VERSION 5.7 ;
BUSBITCHARS "[]" ;
DIVIDERCHAR "/" ;

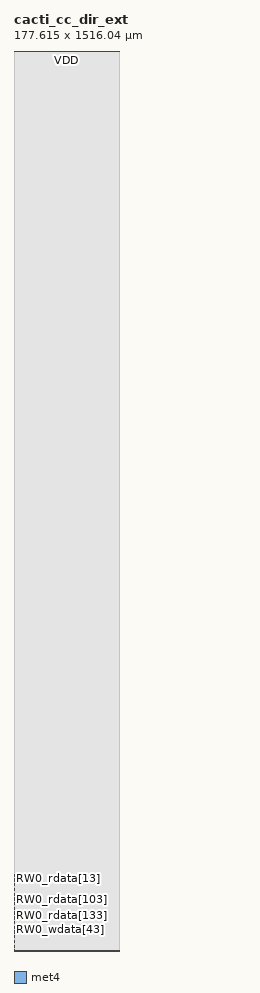
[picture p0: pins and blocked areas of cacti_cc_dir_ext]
MACRO cacti_cc_dir_ext
  CLASS BLOCK BLACKBOX ;
  ORIGIN 0 0 ;
  FOREIGN cacti_cc_dir_ext 0 0 ;
  SIZE 177.615 BY 1516.040 ;
  SYMMETRY X Y ;

  PIN VDD
    DIRECTION INOUT ;
    USE POWER ;
    PORT
      LAYER met4 ;
        RECT 0.000 1515.540 177.615 1516.040 ;
    END
  END VDD
  PIN VSS
    DIRECTION INOUT ;
    USE GROUND ;
    PORT
      LAYER met4 ;
        RECT 0.000 0.000 177.615 0.500 ;
    END
  END VSS
  PIN RW0_clk
    DIRECTION INPUT ;
    USE CLOCK ;
    PORT
      LAYER met4 ;
        RECT 0.000 0.700 0.200 0.900 ;
    END
  END RW0_clk
  PIN RW0_en
    DIRECTION INPUT ;
    USE SIGNAL ;
    PORT
      LAYER met4 ;
        RECT 0.000 1.100 0.200 1.300 ;
    END
  END RW0_en
  PIN RW0_wmode
    DIRECTION INPUT ;
    USE SIGNAL ;
    PORT
      LAYER met4 ;
        RECT 0.000 1.500 0.200 1.700 ;
    END
  END RW0_wmode
  PIN RW0_addr[9]
    DIRECTION INPUT ;
    USE SIGNAL ;
    PORT
      LAYER met4 ;
        RECT 0.000 1.900 0.200 2.100 ;
    END
  END RW0_addr[9]
  PIN RW0_addr[8]
    DIRECTION INPUT ;
    USE SIGNAL ;
    PORT
      LAYER met4 ;
        RECT 0.000 2.300 0.200 2.500 ;
    END
  END RW0_addr[8]
  PIN RW0_addr[7]
    DIRECTION INPUT ;
    USE SIGNAL ;
    PORT
      LAYER met4 ;
        RECT 0.000 2.700 0.200 2.900 ;
    END
  END RW0_addr[7]
  PIN RW0_addr[6]
    DIRECTION INPUT ;
    USE SIGNAL ;
    PORT
      LAYER met4 ;
        RECT 0.000 3.100 0.200 3.300 ;
    END
  END RW0_addr[6]
  PIN RW0_addr[5]
    DIRECTION INPUT ;
    USE SIGNAL ;
    PORT
      LAYER met4 ;
        RECT 0.000 3.500 0.200 3.700 ;
    END
  END RW0_addr[5]
  PIN RW0_addr[4]
    DIRECTION INPUT ;
    USE SIGNAL ;
    PORT
      LAYER met4 ;
        RECT 0.000 3.900 0.200 4.100 ;
    END
  END RW0_addr[4]
  PIN RW0_addr[3]
    DIRECTION INPUT ;
    USE SIGNAL ;
    PORT
      LAYER met4 ;
        RECT 0.000 4.300 0.200 4.500 ;
    END
  END RW0_addr[3]
  PIN RW0_addr[2]
    DIRECTION INPUT ;
    USE SIGNAL ;
    PORT
      LAYER met4 ;
        RECT 0.000 4.700 0.200 4.900 ;
    END
  END RW0_addr[2]
  PIN RW0_addr[1]
    DIRECTION INPUT ;
    USE SIGNAL ;
    PORT
      LAYER met4 ;
        RECT 0.000 5.100 0.200 5.300 ;
    END
  END RW0_addr[1]
  PIN RW0_addr[0]
    DIRECTION INPUT ;
    USE SIGNAL ;
    PORT
      LAYER met4 ;
        RECT 0.000 5.500 0.200 5.700 ;
    END
  END RW0_addr[0]
  PIN RW0_wdata[151]
    DIRECTION INPUT ;
    USE SIGNAL ;
    PORT
      LAYER met4 ;
        RECT 0.000 5.900 0.200 6.100 ;
    END
  END RW0_wdata[151]
  PIN RW0_wdata[150]
    DIRECTION INPUT ;
    USE SIGNAL ;
    PORT
      LAYER met4 ;
        RECT 0.000 6.300 0.200 6.500 ;
    END
  END RW0_wdata[150]
  PIN RW0_wdata[149]
    DIRECTION INPUT ;
    USE SIGNAL ;
    PORT
      LAYER met4 ;
        RECT 0.000 6.700 0.200 6.900 ;
    END
  END RW0_wdata[149]
  PIN RW0_wdata[148]
    DIRECTION INPUT ;
    USE SIGNAL ;
    PORT
      LAYER met4 ;
        RECT 0.000 7.100 0.200 7.300 ;
    END
  END RW0_wdata[148]
  PIN RW0_wdata[147]
    DIRECTION INPUT ;
    USE SIGNAL ;
    PORT
      LAYER met4 ;
        RECT 0.000 7.500 0.200 7.700 ;
    END
  END RW0_wdata[147]
  PIN RW0_wdata[146]
    DIRECTION INPUT ;
    USE SIGNAL ;
    PORT
      LAYER met4 ;
        RECT 0.000 7.900 0.200 8.100 ;
    END
  END RW0_wdata[146]
  PIN RW0_wdata[145]
    DIRECTION INPUT ;
    USE SIGNAL ;
    PORT
      LAYER met4 ;
        RECT 0.000 8.300 0.200 8.500 ;
    END
  END RW0_wdata[145]
  PIN RW0_wdata[144]
    DIRECTION INPUT ;
    USE SIGNAL ;
    PORT
      LAYER met4 ;
        RECT 0.000 8.700 0.200 8.900 ;
    END
  END RW0_wdata[144]
  PIN RW0_wdata[143]
    DIRECTION INPUT ;
    USE SIGNAL ;
    PORT
      LAYER met4 ;
        RECT 0.000 9.100 0.200 9.300 ;
    END
  END RW0_wdata[143]
  PIN RW0_wdata[142]
    DIRECTION INPUT ;
    USE SIGNAL ;
    PORT
      LAYER met4 ;
        RECT 0.000 9.500 0.200 9.700 ;
    END
  END RW0_wdata[142]
  PIN RW0_wdata[141]
    DIRECTION INPUT ;
    USE SIGNAL ;
    PORT
      LAYER met4 ;
        RECT 0.000 9.900 0.200 10.100 ;
    END
  END RW0_wdata[141]
  PIN RW0_wdata[140]
    DIRECTION INPUT ;
    USE SIGNAL ;
    PORT
      LAYER met4 ;
        RECT 0.000 10.300 0.200 10.500 ;
    END
  END RW0_wdata[140]
  PIN RW0_wdata[139]
    DIRECTION INPUT ;
    USE SIGNAL ;
    PORT
      LAYER met4 ;
        RECT 0.000 10.700 0.200 10.900 ;
    END
  END RW0_wdata[139]
  PIN RW0_wdata[138]
    DIRECTION INPUT ;
    USE SIGNAL ;
    PORT
      LAYER met4 ;
        RECT 0.000 11.100 0.200 11.300 ;
    END
  END RW0_wdata[138]
  PIN RW0_wdata[137]
    DIRECTION INPUT ;
    USE SIGNAL ;
    PORT
      LAYER met4 ;
        RECT 0.000 11.500 0.200 11.700 ;
    END
  END RW0_wdata[137]
  PIN RW0_wdata[136]
    DIRECTION INPUT ;
    USE SIGNAL ;
    PORT
      LAYER met4 ;
        RECT 0.000 11.900 0.200 12.100 ;
    END
  END RW0_wdata[136]
  PIN RW0_wdata[135]
    DIRECTION INPUT ;
    USE SIGNAL ;
    PORT
      LAYER met4 ;
        RECT 0.000 12.300 0.200 12.500 ;
    END
  END RW0_wdata[135]
  PIN RW0_wdata[134]
    DIRECTION INPUT ;
    USE SIGNAL ;
    PORT
      LAYER met4 ;
        RECT 0.000 12.700 0.200 12.900 ;
    END
  END RW0_wdata[134]
  PIN RW0_wdata[133]
    DIRECTION INPUT ;
    USE SIGNAL ;
    PORT
      LAYER met4 ;
        RECT 0.000 13.100 0.200 13.300 ;
    END
  END RW0_wdata[133]
  PIN RW0_wdata[132]
    DIRECTION INPUT ;
    USE SIGNAL ;
    PORT
      LAYER met4 ;
        RECT 0.000 13.500 0.200 13.700 ;
    END
  END RW0_wdata[132]
  PIN RW0_wdata[131]
    DIRECTION INPUT ;
    USE SIGNAL ;
    PORT
      LAYER met4 ;
        RECT 0.000 13.900 0.200 14.100 ;
    END
  END RW0_wdata[131]
  PIN RW0_wdata[130]
    DIRECTION INPUT ;
    USE SIGNAL ;
    PORT
      LAYER met4 ;
        RECT 0.000 14.300 0.200 14.500 ;
    END
  END RW0_wdata[130]
  PIN RW0_wdata[129]
    DIRECTION INPUT ;
    USE SIGNAL ;
    PORT
      LAYER met4 ;
        RECT 0.000 14.700 0.200 14.900 ;
    END
  END RW0_wdata[129]
  PIN RW0_wdata[128]
    DIRECTION INPUT ;
    USE SIGNAL ;
    PORT
      LAYER met4 ;
        RECT 0.000 15.100 0.200 15.300 ;
    END
  END RW0_wdata[128]
  PIN RW0_wdata[127]
    DIRECTION INPUT ;
    USE SIGNAL ;
    PORT
      LAYER met4 ;
        RECT 0.000 15.500 0.200 15.700 ;
    END
  END RW0_wdata[127]
  PIN RW0_wdata[126]
    DIRECTION INPUT ;
    USE SIGNAL ;
    PORT
      LAYER met4 ;
        RECT 0.000 15.900 0.200 16.100 ;
    END
  END RW0_wdata[126]
  PIN RW0_wdata[125]
    DIRECTION INPUT ;
    USE SIGNAL ;
    PORT
      LAYER met4 ;
        RECT 0.000 16.300 0.200 16.500 ;
    END
  END RW0_wdata[125]
  PIN RW0_wdata[124]
    DIRECTION INPUT ;
    USE SIGNAL ;
    PORT
      LAYER met4 ;
        RECT 0.000 16.700 0.200 16.900 ;
    END
  END RW0_wdata[124]
  PIN RW0_wdata[123]
    DIRECTION INPUT ;
    USE SIGNAL ;
    PORT
      LAYER met4 ;
        RECT 0.000 17.100 0.200 17.300 ;
    END
  END RW0_wdata[123]
  PIN RW0_wdata[122]
    DIRECTION INPUT ;
    USE SIGNAL ;
    PORT
      LAYER met4 ;
        RECT 0.000 17.500 0.200 17.700 ;
    END
  END RW0_wdata[122]
  PIN RW0_wdata[121]
    DIRECTION INPUT ;
    USE SIGNAL ;
    PORT
      LAYER met4 ;
        RECT 0.000 17.900 0.200 18.100 ;
    END
  END RW0_wdata[121]
  PIN RW0_wdata[120]
    DIRECTION INPUT ;
    USE SIGNAL ;
    PORT
      LAYER met4 ;
        RECT 0.000 18.300 0.200 18.500 ;
    END
  END RW0_wdata[120]
  PIN RW0_wdata[119]
    DIRECTION INPUT ;
    USE SIGNAL ;
    PORT
      LAYER met4 ;
        RECT 0.000 18.700 0.200 18.900 ;
    END
  END RW0_wdata[119]
  PIN RW0_wdata[118]
    DIRECTION INPUT ;
    USE SIGNAL ;
    PORT
      LAYER met4 ;
        RECT 0.000 19.100 0.200 19.300 ;
    END
  END RW0_wdata[118]
  PIN RW0_wdata[117]
    DIRECTION INPUT ;
    USE SIGNAL ;
    PORT
      LAYER met4 ;
        RECT 0.000 19.500 0.200 19.700 ;
    END
  END RW0_wdata[117]
  PIN RW0_wdata[116]
    DIRECTION INPUT ;
    USE SIGNAL ;
    PORT
      LAYER met4 ;
        RECT 0.000 19.900 0.200 20.100 ;
    END
  END RW0_wdata[116]
  PIN RW0_wdata[115]
    DIRECTION INPUT ;
    USE SIGNAL ;
    PORT
      LAYER met4 ;
        RECT 0.000 20.300 0.200 20.500 ;
    END
  END RW0_wdata[115]
  PIN RW0_wdata[114]
    DIRECTION INPUT ;
    USE SIGNAL ;
    PORT
      LAYER met4 ;
        RECT 0.000 20.700 0.200 20.900 ;
    END
  END RW0_wdata[114]
  PIN RW0_wdata[113]
    DIRECTION INPUT ;
    USE SIGNAL ;
    PORT
      LAYER met4 ;
        RECT 0.000 21.100 0.200 21.300 ;
    END
  END RW0_wdata[113]
  PIN RW0_wdata[112]
    DIRECTION INPUT ;
    USE SIGNAL ;
    PORT
      LAYER met4 ;
        RECT 0.000 21.500 0.200 21.700 ;
    END
  END RW0_wdata[112]
  PIN RW0_wdata[111]
    DIRECTION INPUT ;
    USE SIGNAL ;
    PORT
      LAYER met4 ;
        RECT 0.000 21.900 0.200 22.100 ;
    END
  END RW0_wdata[111]
  PIN RW0_wdata[110]
    DIRECTION INPUT ;
    USE SIGNAL ;
    PORT
      LAYER met4 ;
        RECT 0.000 22.300 0.200 22.500 ;
    END
  END RW0_wdata[110]
  PIN RW0_wdata[109]
    DIRECTION INPUT ;
    USE SIGNAL ;
    PORT
      LAYER met4 ;
        RECT 0.000 22.700 0.200 22.900 ;
    END
  END RW0_wdata[109]
  PIN RW0_wdata[108]
    DIRECTION INPUT ;
    USE SIGNAL ;
    PORT
      LAYER met4 ;
        RECT 0.000 23.100 0.200 23.300 ;
    END
  END RW0_wdata[108]
  PIN RW0_wdata[107]
    DIRECTION INPUT ;
    USE SIGNAL ;
    PORT
      LAYER met4 ;
        RECT 0.000 23.500 0.200 23.700 ;
    END
  END RW0_wdata[107]
  PIN RW0_wdata[106]
    DIRECTION INPUT ;
    USE SIGNAL ;
    PORT
      LAYER met4 ;
        RECT 0.000 23.900 0.200 24.100 ;
    END
  END RW0_wdata[106]
  PIN RW0_wdata[105]
    DIRECTION INPUT ;
    USE SIGNAL ;
    PORT
      LAYER met4 ;
        RECT 0.000 24.300 0.200 24.500 ;
    END
  END RW0_wdata[105]
  PIN RW0_wdata[104]
    DIRECTION INPUT ;
    USE SIGNAL ;
    PORT
      LAYER met4 ;
        RECT 0.000 24.700 0.200 24.900 ;
    END
  END RW0_wdata[104]
  PIN RW0_wdata[103]
    DIRECTION INPUT ;
    USE SIGNAL ;
    PORT
      LAYER met4 ;
        RECT 0.000 25.100 0.200 25.300 ;
    END
  END RW0_wdata[103]
  PIN RW0_wdata[102]
    DIRECTION INPUT ;
    USE SIGNAL ;
    PORT
      LAYER met4 ;
        RECT 0.000 25.500 0.200 25.700 ;
    END
  END RW0_wdata[102]
  PIN RW0_wdata[101]
    DIRECTION INPUT ;
    USE SIGNAL ;
    PORT
      LAYER met4 ;
        RECT 0.000 25.900 0.200 26.100 ;
    END
  END RW0_wdata[101]
  PIN RW0_wdata[100]
    DIRECTION INPUT ;
    USE SIGNAL ;
    PORT
      LAYER met4 ;
        RECT 0.000 26.300 0.200 26.500 ;
    END
  END RW0_wdata[100]
  PIN RW0_wdata[99]
    DIRECTION INPUT ;
    USE SIGNAL ;
    PORT
      LAYER met4 ;
        RECT 0.000 26.700 0.200 26.900 ;
    END
  END RW0_wdata[99]
  PIN RW0_wdata[98]
    DIRECTION INPUT ;
    USE SIGNAL ;
    PORT
      LAYER met4 ;
        RECT 0.000 27.100 0.200 27.300 ;
    END
  END RW0_wdata[98]
  PIN RW0_wdata[97]
    DIRECTION INPUT ;
    USE SIGNAL ;
    PORT
      LAYER met4 ;
        RECT 0.000 27.500 0.200 27.700 ;
    END
  END RW0_wdata[97]
  PIN RW0_wdata[96]
    DIRECTION INPUT ;
    USE SIGNAL ;
    PORT
      LAYER met4 ;
        RECT 0.000 27.900 0.200 28.100 ;
    END
  END RW0_wdata[96]
  PIN RW0_wdata[95]
    DIRECTION INPUT ;
    USE SIGNAL ;
    PORT
      LAYER met4 ;
        RECT 0.000 28.300 0.200 28.500 ;
    END
  END RW0_wdata[95]
  PIN RW0_wdata[94]
    DIRECTION INPUT ;
    USE SIGNAL ;
    PORT
      LAYER met4 ;
        RECT 0.000 28.700 0.200 28.900 ;
    END
  END RW0_wdata[94]
  PIN RW0_wdata[93]
    DIRECTION INPUT ;
    USE SIGNAL ;
    PORT
      LAYER met4 ;
        RECT 0.000 29.100 0.200 29.300 ;
    END
  END RW0_wdata[93]
  PIN RW0_wdata[92]
    DIRECTION INPUT ;
    USE SIGNAL ;
    PORT
      LAYER met4 ;
        RECT 0.000 29.500 0.200 29.700 ;
    END
  END RW0_wdata[92]
  PIN RW0_wdata[91]
    DIRECTION INPUT ;
    USE SIGNAL ;
    PORT
      LAYER met4 ;
        RECT 0.000 29.900 0.200 30.100 ;
    END
  END RW0_wdata[91]
  PIN RW0_wdata[90]
    DIRECTION INPUT ;
    USE SIGNAL ;
    PORT
      LAYER met4 ;
        RECT 0.000 30.300 0.200 30.500 ;
    END
  END RW0_wdata[90]
  PIN RW0_wdata[89]
    DIRECTION INPUT ;
    USE SIGNAL ;
    PORT
      LAYER met4 ;
        RECT 0.000 30.700 0.200 30.900 ;
    END
  END RW0_wdata[89]
  PIN RW0_wdata[88]
    DIRECTION INPUT ;
    USE SIGNAL ;
    PORT
      LAYER met4 ;
        RECT 0.000 31.100 0.200 31.300 ;
    END
  END RW0_wdata[88]
  PIN RW0_wdata[87]
    DIRECTION INPUT ;
    USE SIGNAL ;
    PORT
      LAYER met4 ;
        RECT 0.000 31.500 0.200 31.700 ;
    END
  END RW0_wdata[87]
  PIN RW0_wdata[86]
    DIRECTION INPUT ;
    USE SIGNAL ;
    PORT
      LAYER met4 ;
        RECT 0.000 31.900 0.200 32.100 ;
    END
  END RW0_wdata[86]
  PIN RW0_wdata[85]
    DIRECTION INPUT ;
    USE SIGNAL ;
    PORT
      LAYER met4 ;
        RECT 0.000 32.300 0.200 32.500 ;
    END
  END RW0_wdata[85]
  PIN RW0_wdata[84]
    DIRECTION INPUT ;
    USE SIGNAL ;
    PORT
      LAYER met4 ;
        RECT 0.000 32.700 0.200 32.900 ;
    END
  END RW0_wdata[84]
  PIN RW0_wdata[83]
    DIRECTION INPUT ;
    USE SIGNAL ;
    PORT
      LAYER met4 ;
        RECT 0.000 33.100 0.200 33.300 ;
    END
  END RW0_wdata[83]
  PIN RW0_wdata[82]
    DIRECTION INPUT ;
    USE SIGNAL ;
    PORT
      LAYER met4 ;
        RECT 0.000 33.500 0.200 33.700 ;
    END
  END RW0_wdata[82]
  PIN RW0_wdata[81]
    DIRECTION INPUT ;
    USE SIGNAL ;
    PORT
      LAYER met4 ;
        RECT 0.000 33.900 0.200 34.100 ;
    END
  END RW0_wdata[81]
  PIN RW0_wdata[80]
    DIRECTION INPUT ;
    USE SIGNAL ;
    PORT
      LAYER met4 ;
        RECT 0.000 34.300 0.200 34.500 ;
    END
  END RW0_wdata[80]
  PIN RW0_wdata[79]
    DIRECTION INPUT ;
    USE SIGNAL ;
    PORT
      LAYER met4 ;
        RECT 0.000 34.700 0.200 34.900 ;
    END
  END RW0_wdata[79]
  PIN RW0_wdata[78]
    DIRECTION INPUT ;
    USE SIGNAL ;
    PORT
      LAYER met4 ;
        RECT 0.000 35.100 0.200 35.300 ;
    END
  END RW0_wdata[78]
  PIN RW0_wdata[77]
    DIRECTION INPUT ;
    USE SIGNAL ;
    PORT
      LAYER met4 ;
        RECT 0.000 35.500 0.200 35.700 ;
    END
  END RW0_wdata[77]
  PIN RW0_wdata[76]
    DIRECTION INPUT ;
    USE SIGNAL ;
    PORT
      LAYER met4 ;
        RECT 0.000 35.900 0.200 36.100 ;
    END
  END RW0_wdata[76]
  PIN RW0_wdata[75]
    DIRECTION INPUT ;
    USE SIGNAL ;
    PORT
      LAYER met4 ;
        RECT 0.000 36.300 0.200 36.500 ;
    END
  END RW0_wdata[75]
  PIN RW0_wdata[74]
    DIRECTION INPUT ;
    USE SIGNAL ;
    PORT
      LAYER met4 ;
        RECT 0.000 36.700 0.200 36.900 ;
    END
  END RW0_wdata[74]
  PIN RW0_wdata[73]
    DIRECTION INPUT ;
    USE SIGNAL ;
    PORT
      LAYER met4 ;
        RECT 0.000 37.100 0.200 37.300 ;
    END
  END RW0_wdata[73]
  PIN RW0_wdata[72]
    DIRECTION INPUT ;
    USE SIGNAL ;
    PORT
      LAYER met4 ;
        RECT 0.000 37.500 0.200 37.700 ;
    END
  END RW0_wdata[72]
  PIN RW0_wdata[71]
    DIRECTION INPUT ;
    USE SIGNAL ;
    PORT
      LAYER met4 ;
        RECT 0.000 37.900 0.200 38.100 ;
    END
  END RW0_wdata[71]
  PIN RW0_wdata[70]
    DIRECTION INPUT ;
    USE SIGNAL ;
    PORT
      LAYER met4 ;
        RECT 0.000 38.300 0.200 38.500 ;
    END
  END RW0_wdata[70]
  PIN RW0_wdata[69]
    DIRECTION INPUT ;
    USE SIGNAL ;
    PORT
      LAYER met4 ;
        RECT 0.000 38.700 0.200 38.900 ;
    END
  END RW0_wdata[69]
  PIN RW0_wdata[68]
    DIRECTION INPUT ;
    USE SIGNAL ;
    PORT
      LAYER met4 ;
        RECT 0.000 39.100 0.200 39.300 ;
    END
  END RW0_wdata[68]
  PIN RW0_wdata[67]
    DIRECTION INPUT ;
    USE SIGNAL ;
    PORT
      LAYER met4 ;
        RECT 0.000 39.500 0.200 39.700 ;
    END
  END RW0_wdata[67]
  PIN RW0_wdata[66]
    DIRECTION INPUT ;
    USE SIGNAL ;
    PORT
      LAYER met4 ;
        RECT 0.000 39.900 0.200 40.100 ;
    END
  END RW0_wdata[66]
  PIN RW0_wdata[65]
    DIRECTION INPUT ;
    USE SIGNAL ;
    PORT
      LAYER met4 ;
        RECT 0.000 40.300 0.200 40.500 ;
    END
  END RW0_wdata[65]
  PIN RW0_wdata[64]
    DIRECTION INPUT ;
    USE SIGNAL ;
    PORT
      LAYER met4 ;
        RECT 0.000 40.700 0.200 40.900 ;
    END
  END RW0_wdata[64]
  PIN RW0_wdata[63]
    DIRECTION INPUT ;
    USE SIGNAL ;
    PORT
      LAYER met4 ;
        RECT 0.000 41.100 0.200 41.300 ;
    END
  END RW0_wdata[63]
  PIN RW0_wdata[62]
    DIRECTION INPUT ;
    USE SIGNAL ;
    PORT
      LAYER met4 ;
        RECT 0.000 41.500 0.200 41.700 ;
    END
  END RW0_wdata[62]
  PIN RW0_wdata[61]
    DIRECTION INPUT ;
    USE SIGNAL ;
    PORT
      LAYER met4 ;
        RECT 0.000 41.900 0.200 42.100 ;
    END
  END RW0_wdata[61]
  PIN RW0_wdata[60]
    DIRECTION INPUT ;
    USE SIGNAL ;
    PORT
      LAYER met4 ;
        RECT 0.000 42.300 0.200 42.500 ;
    END
  END RW0_wdata[60]
  PIN RW0_wdata[59]
    DIRECTION INPUT ;
    USE SIGNAL ;
    PORT
      LAYER met4 ;
        RECT 0.000 42.700 0.200 42.900 ;
    END
  END RW0_wdata[59]
  PIN RW0_wdata[58]
    DIRECTION INPUT ;
    USE SIGNAL ;
    PORT
      LAYER met4 ;
        RECT 0.000 43.100 0.200 43.300 ;
    END
  END RW0_wdata[58]
  PIN RW0_wdata[57]
    DIRECTION INPUT ;
    USE SIGNAL ;
    PORT
      LAYER met4 ;
        RECT 0.000 43.500 0.200 43.700 ;
    END
  END RW0_wdata[57]
  PIN RW0_wdata[56]
    DIRECTION INPUT ;
    USE SIGNAL ;
    PORT
      LAYER met4 ;
        RECT 0.000 43.900 0.200 44.100 ;
    END
  END RW0_wdata[56]
  PIN RW0_wdata[55]
    DIRECTION INPUT ;
    USE SIGNAL ;
    PORT
      LAYER met4 ;
        RECT 0.000 44.300 0.200 44.500 ;
    END
  END RW0_wdata[55]
  PIN RW0_wdata[54]
    DIRECTION INPUT ;
    USE SIGNAL ;
    PORT
      LAYER met4 ;
        RECT 0.000 44.700 0.200 44.900 ;
    END
  END RW0_wdata[54]
  PIN RW0_wdata[53]
    DIRECTION INPUT ;
    USE SIGNAL ;
    PORT
      LAYER met4 ;
        RECT 0.000 45.100 0.200 45.300 ;
    END
  END RW0_wdata[53]
  PIN RW0_wdata[52]
    DIRECTION INPUT ;
    USE SIGNAL ;
    PORT
      LAYER met4 ;
        RECT 0.000 45.500 0.200 45.700 ;
    END
  END RW0_wdata[52]
  PIN RW0_wdata[51]
    DIRECTION INPUT ;
    USE SIGNAL ;
    PORT
      LAYER met4 ;
        RECT 0.000 45.900 0.200 46.100 ;
    END
  END RW0_wdata[51]
  PIN RW0_wdata[50]
    DIRECTION INPUT ;
    USE SIGNAL ;
    PORT
      LAYER met4 ;
        RECT 0.000 46.300 0.200 46.500 ;
    END
  END RW0_wdata[50]
  PIN RW0_wdata[49]
    DIRECTION INPUT ;
    USE SIGNAL ;
    PORT
      LAYER met4 ;
        RECT 0.000 46.700 0.200 46.900 ;
    END
  END RW0_wdata[49]
  PIN RW0_wdata[48]
    DIRECTION INPUT ;
    USE SIGNAL ;
    PORT
      LAYER met4 ;
        RECT 0.000 47.100 0.200 47.300 ;
    END
  END RW0_wdata[48]
  PIN RW0_wdata[47]
    DIRECTION INPUT ;
    USE SIGNAL ;
    PORT
      LAYER met4 ;
        RECT 0.000 47.500 0.200 47.700 ;
    END
  END RW0_wdata[47]
  PIN RW0_wdata[46]
    DIRECTION INPUT ;
    USE SIGNAL ;
    PORT
      LAYER met4 ;
        RECT 0.000 47.900 0.200 48.100 ;
    END
  END RW0_wdata[46]
  PIN RW0_wdata[45]
    DIRECTION INPUT ;
    USE SIGNAL ;
    PORT
      LAYER met4 ;
        RECT 0.000 48.300 0.200 48.500 ;
    END
  END RW0_wdata[45]
  PIN RW0_wdata[44]
    DIRECTION INPUT ;
    USE SIGNAL ;
    PORT
      LAYER met4 ;
        RECT 0.000 48.700 0.200 48.900 ;
    END
  END RW0_wdata[44]
  PIN RW0_wdata[43]
    DIRECTION INPUT ;
    USE SIGNAL ;
    PORT
      LAYER met4 ;
        RECT 0.000 49.100 0.200 49.300 ;
    END
  END RW0_wdata[43]
  PIN RW0_wdata[42]
    DIRECTION INPUT ;
    USE SIGNAL ;
    PORT
      LAYER met4 ;
        RECT 0.000 49.500 0.200 49.700 ;
    END
  END RW0_wdata[42]
  PIN RW0_wdata[41]
    DIRECTION INPUT ;
    USE SIGNAL ;
    PORT
      LAYER met4 ;
        RECT 0.000 49.900 0.200 50.100 ;
    END
  END RW0_wdata[41]
  PIN RW0_wdata[40]
    DIRECTION INPUT ;
    USE SIGNAL ;
    PORT
      LAYER met4 ;
        RECT 0.000 50.300 0.200 50.500 ;
    END
  END RW0_wdata[40]
  PIN RW0_wdata[39]
    DIRECTION INPUT ;
    USE SIGNAL ;
    PORT
      LAYER met4 ;
        RECT 0.000 50.700 0.200 50.900 ;
    END
  END RW0_wdata[39]
  PIN RW0_wdata[38]
    DIRECTION INPUT ;
    USE SIGNAL ;
    PORT
      LAYER met4 ;
        RECT 0.000 51.100 0.200 51.300 ;
    END
  END RW0_wdata[38]
  PIN RW0_wdata[37]
    DIRECTION INPUT ;
    USE SIGNAL ;
    PORT
      LAYER met4 ;
        RECT 0.000 51.500 0.200 51.700 ;
    END
  END RW0_wdata[37]
  PIN RW0_wdata[36]
    DIRECTION INPUT ;
    USE SIGNAL ;
    PORT
      LAYER met4 ;
        RECT 0.000 51.900 0.200 52.100 ;
    END
  END RW0_wdata[36]
  PIN RW0_wdata[35]
    DIRECTION INPUT ;
    USE SIGNAL ;
    PORT
      LAYER met4 ;
        RECT 0.000 52.300 0.200 52.500 ;
    END
  END RW0_wdata[35]
  PIN RW0_wdata[34]
    DIRECTION INPUT ;
    USE SIGNAL ;
    PORT
      LAYER met4 ;
        RECT 0.000 52.700 0.200 52.900 ;
    END
  END RW0_wdata[34]
  PIN RW0_wdata[33]
    DIRECTION INPUT ;
    USE SIGNAL ;
    PORT
      LAYER met4 ;
        RECT 0.000 53.100 0.200 53.300 ;
    END
  END RW0_wdata[33]
  PIN RW0_wdata[32]
    DIRECTION INPUT ;
    USE SIGNAL ;
    PORT
      LAYER met4 ;
        RECT 0.000 53.500 0.200 53.700 ;
    END
  END RW0_wdata[32]
  PIN RW0_wdata[31]
    DIRECTION INPUT ;
    USE SIGNAL ;
    PORT
      LAYER met4 ;
        RECT 0.000 53.900 0.200 54.100 ;
    END
  END RW0_wdata[31]
  PIN RW0_wdata[30]
    DIRECTION INPUT ;
    USE SIGNAL ;
    PORT
      LAYER met4 ;
        RECT 0.000 54.300 0.200 54.500 ;
    END
  END RW0_wdata[30]
  PIN RW0_wdata[29]
    DIRECTION INPUT ;
    USE SIGNAL ;
    PORT
      LAYER met4 ;
        RECT 0.000 54.700 0.200 54.900 ;
    END
  END RW0_wdata[29]
  PIN RW0_wdata[28]
    DIRECTION INPUT ;
    USE SIGNAL ;
    PORT
      LAYER met4 ;
        RECT 0.000 55.100 0.200 55.300 ;
    END
  END RW0_wdata[28]
  PIN RW0_wdata[27]
    DIRECTION INPUT ;
    USE SIGNAL ;
    PORT
      LAYER met4 ;
        RECT 0.000 55.500 0.200 55.700 ;
    END
  END RW0_wdata[27]
  PIN RW0_wdata[26]
    DIRECTION INPUT ;
    USE SIGNAL ;
    PORT
      LAYER met4 ;
        RECT 0.000 55.900 0.200 56.100 ;
    END
  END RW0_wdata[26]
  PIN RW0_wdata[25]
    DIRECTION INPUT ;
    USE SIGNAL ;
    PORT
      LAYER met4 ;
        RECT 0.000 56.300 0.200 56.500 ;
    END
  END RW0_wdata[25]
  PIN RW0_wdata[24]
    DIRECTION INPUT ;
    USE SIGNAL ;
    PORT
      LAYER met4 ;
        RECT 0.000 56.700 0.200 56.900 ;
    END
  END RW0_wdata[24]
  PIN RW0_wdata[23]
    DIRECTION INPUT ;
    USE SIGNAL ;
    PORT
      LAYER met4 ;
        RECT 0.000 57.100 0.200 57.300 ;
    END
  END RW0_wdata[23]
  PIN RW0_wdata[22]
    DIRECTION INPUT ;
    USE SIGNAL ;
    PORT
      LAYER met4 ;
        RECT 0.000 57.500 0.200 57.700 ;
    END
  END RW0_wdata[22]
  PIN RW0_wdata[21]
    DIRECTION INPUT ;
    USE SIGNAL ;
    PORT
      LAYER met4 ;
        RECT 0.000 57.900 0.200 58.100 ;
    END
  END RW0_wdata[21]
  PIN RW0_wdata[20]
    DIRECTION INPUT ;
    USE SIGNAL ;
    PORT
      LAYER met4 ;
        RECT 0.000 58.300 0.200 58.500 ;
    END
  END RW0_wdata[20]
  PIN RW0_wdata[19]
    DIRECTION INPUT ;
    USE SIGNAL ;
    PORT
      LAYER met4 ;
        RECT 0.000 58.700 0.200 58.900 ;
    END
  END RW0_wdata[19]
  PIN RW0_wdata[18]
    DIRECTION INPUT ;
    USE SIGNAL ;
    PORT
      LAYER met4 ;
        RECT 0.000 59.100 0.200 59.300 ;
    END
  END RW0_wdata[18]
  PIN RW0_wdata[17]
    DIRECTION INPUT ;
    USE SIGNAL ;
    PORT
      LAYER met4 ;
        RECT 0.000 59.500 0.200 59.700 ;
    END
  END RW0_wdata[17]
  PIN RW0_wdata[16]
    DIRECTION INPUT ;
    USE SIGNAL ;
    PORT
      LAYER met4 ;
        RECT 0.000 59.900 0.200 60.100 ;
    END
  END RW0_wdata[16]
  PIN RW0_wdata[15]
    DIRECTION INPUT ;
    USE SIGNAL ;
    PORT
      LAYER met4 ;
        RECT 0.000 60.300 0.200 60.500 ;
    END
  END RW0_wdata[15]
  PIN RW0_wdata[14]
    DIRECTION INPUT ;
    USE SIGNAL ;
    PORT
      LAYER met4 ;
        RECT 0.000 60.700 0.200 60.900 ;
    END
  END RW0_wdata[14]
  PIN RW0_wdata[13]
    DIRECTION INPUT ;
    USE SIGNAL ;
    PORT
      LAYER met4 ;
        RECT 0.000 61.100 0.200 61.300 ;
    END
  END RW0_wdata[13]
  PIN RW0_wdata[12]
    DIRECTION INPUT ;
    USE SIGNAL ;
    PORT
      LAYER met4 ;
        RECT 0.000 61.500 0.200 61.700 ;
    END
  END RW0_wdata[12]
  PIN RW0_wdata[11]
    DIRECTION INPUT ;
    USE SIGNAL ;
    PORT
      LAYER met4 ;
        RECT 0.000 61.900 0.200 62.100 ;
    END
  END RW0_wdata[11]
  PIN RW0_wdata[10]
    DIRECTION INPUT ;
    USE SIGNAL ;
    PORT
      LAYER met4 ;
        RECT 0.000 62.300 0.200 62.500 ;
    END
  END RW0_wdata[10]
  PIN RW0_wdata[9]
    DIRECTION INPUT ;
    USE SIGNAL ;
    PORT
      LAYER met4 ;
        RECT 0.000 62.700 0.200 62.900 ;
    END
  END RW0_wdata[9]
  PIN RW0_wdata[8]
    DIRECTION INPUT ;
    USE SIGNAL ;
    PORT
      LAYER met4 ;
        RECT 0.000 63.100 0.200 63.300 ;
    END
  END RW0_wdata[8]
  PIN RW0_wdata[7]
    DIRECTION INPUT ;
    USE SIGNAL ;
    PORT
      LAYER met4 ;
        RECT 0.000 63.500 0.200 63.700 ;
    END
  END RW0_wdata[7]
  PIN RW0_wdata[6]
    DIRECTION INPUT ;
    USE SIGNAL ;
    PORT
      LAYER met4 ;
        RECT 0.000 63.900 0.200 64.100 ;
    END
  END RW0_wdata[6]
  PIN RW0_wdata[5]
    DIRECTION INPUT ;
    USE SIGNAL ;
    PORT
      LAYER met4 ;
        RECT 0.000 64.300 0.200 64.500 ;
    END
  END RW0_wdata[5]
  PIN RW0_wdata[4]
    DIRECTION INPUT ;
    USE SIGNAL ;
    PORT
      LAYER met4 ;
        RECT 0.000 64.700 0.200 64.900 ;
    END
  END RW0_wdata[4]
  PIN RW0_wdata[3]
    DIRECTION INPUT ;
    USE SIGNAL ;
    PORT
      LAYER met4 ;
        RECT 0.000 65.100 0.200 65.300 ;
    END
  END RW0_wdata[3]
  PIN RW0_wdata[2]
    DIRECTION INPUT ;
    USE SIGNAL ;
    PORT
      LAYER met4 ;
        RECT 0.000 65.500 0.200 65.700 ;
    END
  END RW0_wdata[2]
  PIN RW0_wdata[1]
    DIRECTION INPUT ;
    USE SIGNAL ;
    PORT
      LAYER met4 ;
        RECT 0.000 65.900 0.200 66.100 ;
    END
  END RW0_wdata[1]
  PIN RW0_wdata[0]
    DIRECTION INPUT ;
    USE SIGNAL ;
    PORT
      LAYER met4 ;
        RECT 0.000 66.300 0.200 66.500 ;
    END
  END RW0_wdata[0]
  PIN RW0_rdata[151]
    DIRECTION OUTPUT ;
    USE SIGNAL ;
    PORT
      LAYER met4 ;
        RECT 0.000 66.700 0.200 66.900 ;
    END
  END RW0_rdata[151]
  PIN RW0_rdata[150]
    DIRECTION OUTPUT ;
    USE SIGNAL ;
    PORT
      LAYER met4 ;
        RECT 0.000 67.100 0.200 67.300 ;
    END
  END RW0_rdata[150]
  PIN RW0_rdata[149]
    DIRECTION OUTPUT ;
    USE SIGNAL ;
    PORT
      LAYER met4 ;
        RECT 0.000 67.500 0.200 67.700 ;
    END
  END RW0_rdata[149]
  PIN RW0_rdata[148]
    DIRECTION OUTPUT ;
    USE SIGNAL ;
    PORT
      LAYER met4 ;
        RECT 0.000 67.900 0.200 68.100 ;
    END
  END RW0_rdata[148]
  PIN RW0_rdata[147]
    DIRECTION OUTPUT ;
    USE SIGNAL ;
    PORT
      LAYER met4 ;
        RECT 0.000 68.300 0.200 68.500 ;
    END
  END RW0_rdata[147]
  PIN RW0_rdata[146]
    DIRECTION OUTPUT ;
    USE SIGNAL ;
    PORT
      LAYER met4 ;
        RECT 0.000 68.700 0.200 68.900 ;
    END
  END RW0_rdata[146]
  PIN RW0_rdata[145]
    DIRECTION OUTPUT ;
    USE SIGNAL ;
    PORT
      LAYER met4 ;
        RECT 0.000 69.100 0.200 69.300 ;
    END
  END RW0_rdata[145]
  PIN RW0_rdata[144]
    DIRECTION OUTPUT ;
    USE SIGNAL ;
    PORT
      LAYER met4 ;
        RECT 0.000 69.500 0.200 69.700 ;
    END
  END RW0_rdata[144]
  PIN RW0_rdata[143]
    DIRECTION OUTPUT ;
    USE SIGNAL ;
    PORT
      LAYER met4 ;
        RECT 0.000 69.900 0.200 70.100 ;
    END
  END RW0_rdata[143]
  PIN RW0_rdata[142]
    DIRECTION OUTPUT ;
    USE SIGNAL ;
    PORT
      LAYER met4 ;
        RECT 0.000 70.300 0.200 70.500 ;
    END
  END RW0_rdata[142]
  PIN RW0_rdata[141]
    DIRECTION OUTPUT ;
    USE SIGNAL ;
    PORT
      LAYER met4 ;
        RECT 0.000 70.700 0.200 70.900 ;
    END
  END RW0_rdata[141]
  PIN RW0_rdata[140]
    DIRECTION OUTPUT ;
    USE SIGNAL ;
    PORT
      LAYER met4 ;
        RECT 0.000 71.100 0.200 71.300 ;
    END
  END RW0_rdata[140]
  PIN RW0_rdata[139]
    DIRECTION OUTPUT ;
    USE SIGNAL ;
    PORT
      LAYER met4 ;
        RECT 0.000 71.500 0.200 71.700 ;
    END
  END RW0_rdata[139]
  PIN RW0_rdata[138]
    DIRECTION OUTPUT ;
    USE SIGNAL ;
    PORT
      LAYER met4 ;
        RECT 0.000 71.900 0.200 72.100 ;
    END
  END RW0_rdata[138]
  PIN RW0_rdata[137]
    DIRECTION OUTPUT ;
    USE SIGNAL ;
    PORT
      LAYER met4 ;
        RECT 0.000 72.300 0.200 72.500 ;
    END
  END RW0_rdata[137]
  PIN RW0_rdata[136]
    DIRECTION OUTPUT ;
    USE SIGNAL ;
    PORT
      LAYER met4 ;
        RECT 0.000 72.700 0.200 72.900 ;
    END
  END RW0_rdata[136]
  PIN RW0_rdata[135]
    DIRECTION OUTPUT ;
    USE SIGNAL ;
    PORT
      LAYER met4 ;
        RECT 0.000 73.100 0.200 73.300 ;
    END
  END RW0_rdata[135]
  PIN RW0_rdata[134]
    DIRECTION OUTPUT ;
    USE SIGNAL ;
    PORT
      LAYER met4 ;
        RECT 0.000 73.500 0.200 73.700 ;
    END
  END RW0_rdata[134]
  PIN RW0_rdata[133]
    DIRECTION OUTPUT ;
    USE SIGNAL ;
    PORT
      LAYER met4 ;
        RECT 0.000 73.900 0.200 74.100 ;
    END
  END RW0_rdata[133]
  PIN RW0_rdata[132]
    DIRECTION OUTPUT ;
    USE SIGNAL ;
    PORT
      LAYER met4 ;
        RECT 0.000 74.300 0.200 74.500 ;
    END
  END RW0_rdata[132]
  PIN RW0_rdata[131]
    DIRECTION OUTPUT ;
    USE SIGNAL ;
    PORT
      LAYER met4 ;
        RECT 0.000 74.700 0.200 74.900 ;
    END
  END RW0_rdata[131]
  PIN RW0_rdata[130]
    DIRECTION OUTPUT ;
    USE SIGNAL ;
    PORT
      LAYER met4 ;
        RECT 0.000 75.100 0.200 75.300 ;
    END
  END RW0_rdata[130]
  PIN RW0_rdata[129]
    DIRECTION OUTPUT ;
    USE SIGNAL ;
    PORT
      LAYER met4 ;
        RECT 0.000 75.500 0.200 75.700 ;
    END
  END RW0_rdata[129]
  PIN RW0_rdata[128]
    DIRECTION OUTPUT ;
    USE SIGNAL ;
    PORT
      LAYER met4 ;
        RECT 0.000 75.900 0.200 76.100 ;
    END
  END RW0_rdata[128]
  PIN RW0_rdata[127]
    DIRECTION OUTPUT ;
    USE SIGNAL ;
    PORT
      LAYER met4 ;
        RECT 0.000 76.300 0.200 76.500 ;
    END
  END RW0_rdata[127]
  PIN RW0_rdata[126]
    DIRECTION OUTPUT ;
    USE SIGNAL ;
    PORT
      LAYER met4 ;
        RECT 0.000 76.700 0.200 76.900 ;
    END
  END RW0_rdata[126]
  PIN RW0_rdata[125]
    DIRECTION OUTPUT ;
    USE SIGNAL ;
    PORT
      LAYER met4 ;
        RECT 0.000 77.100 0.200 77.300 ;
    END
  END RW0_rdata[125]
  PIN RW0_rdata[124]
    DIRECTION OUTPUT ;
    USE SIGNAL ;
    PORT
      LAYER met4 ;
        RECT 0.000 77.500 0.200 77.700 ;
    END
  END RW0_rdata[124]
  PIN RW0_rdata[123]
    DIRECTION OUTPUT ;
    USE SIGNAL ;
    PORT
      LAYER met4 ;
        RECT 0.000 77.900 0.200 78.100 ;
    END
  END RW0_rdata[123]
  PIN RW0_rdata[122]
    DIRECTION OUTPUT ;
    USE SIGNAL ;
    PORT
      LAYER met4 ;
        RECT 0.000 78.300 0.200 78.500 ;
    END
  END RW0_rdata[122]
  PIN RW0_rdata[121]
    DIRECTION OUTPUT ;
    USE SIGNAL ;
    PORT
      LAYER met4 ;
        RECT 0.000 78.700 0.200 78.900 ;
    END
  END RW0_rdata[121]
  PIN RW0_rdata[120]
    DIRECTION OUTPUT ;
    USE SIGNAL ;
    PORT
      LAYER met4 ;
        RECT 0.000 79.100 0.200 79.300 ;
    END
  END RW0_rdata[120]
  PIN RW0_rdata[119]
    DIRECTION OUTPUT ;
    USE SIGNAL ;
    PORT
      LAYER met4 ;
        RECT 0.000 79.500 0.200 79.700 ;
    END
  END RW0_rdata[119]
  PIN RW0_rdata[118]
    DIRECTION OUTPUT ;
    USE SIGNAL ;
    PORT
      LAYER met4 ;
        RECT 0.000 79.900 0.200 80.100 ;
    END
  END RW0_rdata[118]
  PIN RW0_rdata[117]
    DIRECTION OUTPUT ;
    USE SIGNAL ;
    PORT
      LAYER met4 ;
        RECT 0.000 80.300 0.200 80.500 ;
    END
  END RW0_rdata[117]
  PIN RW0_rdata[116]
    DIRECTION OUTPUT ;
    USE SIGNAL ;
    PORT
      LAYER met4 ;
        RECT 0.000 80.700 0.200 80.900 ;
    END
  END RW0_rdata[116]
  PIN RW0_rdata[115]
    DIRECTION OUTPUT ;
    USE SIGNAL ;
    PORT
      LAYER met4 ;
        RECT 0.000 81.100 0.200 81.300 ;
    END
  END RW0_rdata[115]
  PIN RW0_rdata[114]
    DIRECTION OUTPUT ;
    USE SIGNAL ;
    PORT
      LAYER met4 ;
        RECT 0.000 81.500 0.200 81.700 ;
    END
  END RW0_rdata[114]
  PIN RW0_rdata[113]
    DIRECTION OUTPUT ;
    USE SIGNAL ;
    PORT
      LAYER met4 ;
        RECT 0.000 81.900 0.200 82.100 ;
    END
  END RW0_rdata[113]
  PIN RW0_rdata[112]
    DIRECTION OUTPUT ;
    USE SIGNAL ;
    PORT
      LAYER met4 ;
        RECT 0.000 82.300 0.200 82.500 ;
    END
  END RW0_rdata[112]
  PIN RW0_rdata[111]
    DIRECTION OUTPUT ;
    USE SIGNAL ;
    PORT
      LAYER met4 ;
        RECT 0.000 82.700 0.200 82.900 ;
    END
  END RW0_rdata[111]
  PIN RW0_rdata[110]
    DIRECTION OUTPUT ;
    USE SIGNAL ;
    PORT
      LAYER met4 ;
        RECT 0.000 83.100 0.200 83.300 ;
    END
  END RW0_rdata[110]
  PIN RW0_rdata[109]
    DIRECTION OUTPUT ;
    USE SIGNAL ;
    PORT
      LAYER met4 ;
        RECT 0.000 83.500 0.200 83.700 ;
    END
  END RW0_rdata[109]
  PIN RW0_rdata[108]
    DIRECTION OUTPUT ;
    USE SIGNAL ;
    PORT
      LAYER met4 ;
        RECT 0.000 83.900 0.200 84.100 ;
    END
  END RW0_rdata[108]
  PIN RW0_rdata[107]
    DIRECTION OUTPUT ;
    USE SIGNAL ;
    PORT
      LAYER met4 ;
        RECT 0.000 84.300 0.200 84.500 ;
    END
  END RW0_rdata[107]
  PIN RW0_rdata[106]
    DIRECTION OUTPUT ;
    USE SIGNAL ;
    PORT
      LAYER met4 ;
        RECT 0.000 84.700 0.200 84.900 ;
    END
  END RW0_rdata[106]
  PIN RW0_rdata[105]
    DIRECTION OUTPUT ;
    USE SIGNAL ;
    PORT
      LAYER met4 ;
        RECT 0.000 85.100 0.200 85.300 ;
    END
  END RW0_rdata[105]
  PIN RW0_rdata[104]
    DIRECTION OUTPUT ;
    USE SIGNAL ;
    PORT
      LAYER met4 ;
        RECT 0.000 85.500 0.200 85.700 ;
    END
  END RW0_rdata[104]
  PIN RW0_rdata[103]
    DIRECTION OUTPUT ;
    USE SIGNAL ;
    PORT
      LAYER met4 ;
        RECT 0.000 85.900 0.200 86.100 ;
    END
  END RW0_rdata[103]
  PIN RW0_rdata[102]
    DIRECTION OUTPUT ;
    USE SIGNAL ;
    PORT
      LAYER met4 ;
        RECT 0.000 86.300 0.200 86.500 ;
    END
  END RW0_rdata[102]
  PIN RW0_rdata[101]
    DIRECTION OUTPUT ;
    USE SIGNAL ;
    PORT
      LAYER met4 ;
        RECT 0.000 86.700 0.200 86.900 ;
    END
  END RW0_rdata[101]
  PIN RW0_rdata[100]
    DIRECTION OUTPUT ;
    USE SIGNAL ;
    PORT
      LAYER met4 ;
        RECT 0.000 87.100 0.200 87.300 ;
    END
  END RW0_rdata[100]
  PIN RW0_rdata[99]
    DIRECTION OUTPUT ;
    USE SIGNAL ;
    PORT
      LAYER met4 ;
        RECT 0.000 87.500 0.200 87.700 ;
    END
  END RW0_rdata[99]
  PIN RW0_rdata[98]
    DIRECTION OUTPUT ;
    USE SIGNAL ;
    PORT
      LAYER met4 ;
        RECT 0.000 87.900 0.200 88.100 ;
    END
  END RW0_rdata[98]
  PIN RW0_rdata[97]
    DIRECTION OUTPUT ;
    USE SIGNAL ;
    PORT
      LAYER met4 ;
        RECT 0.000 88.300 0.200 88.500 ;
    END
  END RW0_rdata[97]
  PIN RW0_rdata[96]
    DIRECTION OUTPUT ;
    USE SIGNAL ;
    PORT
      LAYER met4 ;
        RECT 0.000 88.700 0.200 88.900 ;
    END
  END RW0_rdata[96]
  PIN RW0_rdata[95]
    DIRECTION OUTPUT ;
    USE SIGNAL ;
    PORT
      LAYER met4 ;
        RECT 0.000 89.100 0.200 89.300 ;
    END
  END RW0_rdata[95]
  PIN RW0_rdata[94]
    DIRECTION OUTPUT ;
    USE SIGNAL ;
    PORT
      LAYER met4 ;
        RECT 0.000 89.500 0.200 89.700 ;
    END
  END RW0_rdata[94]
  PIN RW0_rdata[93]
    DIRECTION OUTPUT ;
    USE SIGNAL ;
    PORT
      LAYER met4 ;
        RECT 0.000 89.900 0.200 90.100 ;
    END
  END RW0_rdata[93]
  PIN RW0_rdata[92]
    DIRECTION OUTPUT ;
    USE SIGNAL ;
    PORT
      LAYER met4 ;
        RECT 0.000 90.300 0.200 90.500 ;
    END
  END RW0_rdata[92]
  PIN RW0_rdata[91]
    DIRECTION OUTPUT ;
    USE SIGNAL ;
    PORT
      LAYER met4 ;
        RECT 0.000 90.700 0.200 90.900 ;
    END
  END RW0_rdata[91]
  PIN RW0_rdata[90]
    DIRECTION OUTPUT ;
    USE SIGNAL ;
    PORT
      LAYER met4 ;
        RECT 0.000 91.100 0.200 91.300 ;
    END
  END RW0_rdata[90]
  PIN RW0_rdata[89]
    DIRECTION OUTPUT ;
    USE SIGNAL ;
    PORT
      LAYER met4 ;
        RECT 0.000 91.500 0.200 91.700 ;
    END
  END RW0_rdata[89]
  PIN RW0_rdata[88]
    DIRECTION OUTPUT ;
    USE SIGNAL ;
    PORT
      LAYER met4 ;
        RECT 0.000 91.900 0.200 92.100 ;
    END
  END RW0_rdata[88]
  PIN RW0_rdata[87]
    DIRECTION OUTPUT ;
    USE SIGNAL ;
    PORT
      LAYER met4 ;
        RECT 0.000 92.300 0.200 92.500 ;
    END
  END RW0_rdata[87]
  PIN RW0_rdata[86]
    DIRECTION OUTPUT ;
    USE SIGNAL ;
    PORT
      LAYER met4 ;
        RECT 0.000 92.700 0.200 92.900 ;
    END
  END RW0_rdata[86]
  PIN RW0_rdata[85]
    DIRECTION OUTPUT ;
    USE SIGNAL ;
    PORT
      LAYER met4 ;
        RECT 0.000 93.100 0.200 93.300 ;
    END
  END RW0_rdata[85]
  PIN RW0_rdata[84]
    DIRECTION OUTPUT ;
    USE SIGNAL ;
    PORT
      LAYER met4 ;
        RECT 0.000 93.500 0.200 93.700 ;
    END
  END RW0_rdata[84]
  PIN RW0_rdata[83]
    DIRECTION OUTPUT ;
    USE SIGNAL ;
    PORT
      LAYER met4 ;
        RECT 0.000 93.900 0.200 94.100 ;
    END
  END RW0_rdata[83]
  PIN RW0_rdata[82]
    DIRECTION OUTPUT ;
    USE SIGNAL ;
    PORT
      LAYER met4 ;
        RECT 0.000 94.300 0.200 94.500 ;
    END
  END RW0_rdata[82]
  PIN RW0_rdata[81]
    DIRECTION OUTPUT ;
    USE SIGNAL ;
    PORT
      LAYER met4 ;
        RECT 0.000 94.700 0.200 94.900 ;
    END
  END RW0_rdata[81]
  PIN RW0_rdata[80]
    DIRECTION OUTPUT ;
    USE SIGNAL ;
    PORT
      LAYER met4 ;
        RECT 0.000 95.100 0.200 95.300 ;
    END
  END RW0_rdata[80]
  PIN RW0_rdata[79]
    DIRECTION OUTPUT ;
    USE SIGNAL ;
    PORT
      LAYER met4 ;
        RECT 0.000 95.500 0.200 95.700 ;
    END
  END RW0_rdata[79]
  PIN RW0_rdata[78]
    DIRECTION OUTPUT ;
    USE SIGNAL ;
    PORT
      LAYER met4 ;
        RECT 0.000 95.900 0.200 96.100 ;
    END
  END RW0_rdata[78]
  PIN RW0_rdata[77]
    DIRECTION OUTPUT ;
    USE SIGNAL ;
    PORT
      LAYER met4 ;
        RECT 0.000 96.300 0.200 96.500 ;
    END
  END RW0_rdata[77]
  PIN RW0_rdata[76]
    DIRECTION OUTPUT ;
    USE SIGNAL ;
    PORT
      LAYER met4 ;
        RECT 0.000 96.700 0.200 96.900 ;
    END
  END RW0_rdata[76]
  PIN RW0_rdata[75]
    DIRECTION OUTPUT ;
    USE SIGNAL ;
    PORT
      LAYER met4 ;
        RECT 0.000 97.100 0.200 97.300 ;
    END
  END RW0_rdata[75]
  PIN RW0_rdata[74]
    DIRECTION OUTPUT ;
    USE SIGNAL ;
    PORT
      LAYER met4 ;
        RECT 0.000 97.500 0.200 97.700 ;
    END
  END RW0_rdata[74]
  PIN RW0_rdata[73]
    DIRECTION OUTPUT ;
    USE SIGNAL ;
    PORT
      LAYER met4 ;
        RECT 0.000 97.900 0.200 98.100 ;
    END
  END RW0_rdata[73]
  PIN RW0_rdata[72]
    DIRECTION OUTPUT ;
    USE SIGNAL ;
    PORT
      LAYER met4 ;
        RECT 0.000 98.300 0.200 98.500 ;
    END
  END RW0_rdata[72]
  PIN RW0_rdata[71]
    DIRECTION OUTPUT ;
    USE SIGNAL ;
    PORT
      LAYER met4 ;
        RECT 0.000 98.700 0.200 98.900 ;
    END
  END RW0_rdata[71]
  PIN RW0_rdata[70]
    DIRECTION OUTPUT ;
    USE SIGNAL ;
    PORT
      LAYER met4 ;
        RECT 0.000 99.100 0.200 99.300 ;
    END
  END RW0_rdata[70]
  PIN RW0_rdata[69]
    DIRECTION OUTPUT ;
    USE SIGNAL ;
    PORT
      LAYER met4 ;
        RECT 0.000 99.500 0.200 99.700 ;
    END
  END RW0_rdata[69]
  PIN RW0_rdata[68]
    DIRECTION OUTPUT ;
    USE SIGNAL ;
    PORT
      LAYER met4 ;
        RECT 0.000 99.900 0.200 100.100 ;
    END
  END RW0_rdata[68]
  PIN RW0_rdata[67]
    DIRECTION OUTPUT ;
    USE SIGNAL ;
    PORT
      LAYER met4 ;
        RECT 0.000 100.300 0.200 100.500 ;
    END
  END RW0_rdata[67]
  PIN RW0_rdata[66]
    DIRECTION OUTPUT ;
    USE SIGNAL ;
    PORT
      LAYER met4 ;
        RECT 0.000 100.700 0.200 100.900 ;
    END
  END RW0_rdata[66]
  PIN RW0_rdata[65]
    DIRECTION OUTPUT ;
    USE SIGNAL ;
    PORT
      LAYER met4 ;
        RECT 0.000 101.100 0.200 101.300 ;
    END
  END RW0_rdata[65]
  PIN RW0_rdata[64]
    DIRECTION OUTPUT ;
    USE SIGNAL ;
    PORT
      LAYER met4 ;
        RECT 0.000 101.500 0.200 101.700 ;
    END
  END RW0_rdata[64]
  PIN RW0_rdata[63]
    DIRECTION OUTPUT ;
    USE SIGNAL ;
    PORT
      LAYER met4 ;
        RECT 0.000 101.900 0.200 102.100 ;
    END
  END RW0_rdata[63]
  PIN RW0_rdata[62]
    DIRECTION OUTPUT ;
    USE SIGNAL ;
    PORT
      LAYER met4 ;
        RECT 0.000 102.300 0.200 102.500 ;
    END
  END RW0_rdata[62]
  PIN RW0_rdata[61]
    DIRECTION OUTPUT ;
    USE SIGNAL ;
    PORT
      LAYER met4 ;
        RECT 0.000 102.700 0.200 102.900 ;
    END
  END RW0_rdata[61]
  PIN RW0_rdata[60]
    DIRECTION OUTPUT ;
    USE SIGNAL ;
    PORT
      LAYER met4 ;
        RECT 0.000 103.100 0.200 103.300 ;
    END
  END RW0_rdata[60]
  PIN RW0_rdata[59]
    DIRECTION OUTPUT ;
    USE SIGNAL ;
    PORT
      LAYER met4 ;
        RECT 0.000 103.500 0.200 103.700 ;
    END
  END RW0_rdata[59]
  PIN RW0_rdata[58]
    DIRECTION OUTPUT ;
    USE SIGNAL ;
    PORT
      LAYER met4 ;
        RECT 0.000 103.900 0.200 104.100 ;
    END
  END RW0_rdata[58]
  PIN RW0_rdata[57]
    DIRECTION OUTPUT ;
    USE SIGNAL ;
    PORT
      LAYER met4 ;
        RECT 0.000 104.300 0.200 104.500 ;
    END
  END RW0_rdata[57]
  PIN RW0_rdata[56]
    DIRECTION OUTPUT ;
    USE SIGNAL ;
    PORT
      LAYER met4 ;
        RECT 0.000 104.700 0.200 104.900 ;
    END
  END RW0_rdata[56]
  PIN RW0_rdata[55]
    DIRECTION OUTPUT ;
    USE SIGNAL ;
    PORT
      LAYER met4 ;
        RECT 0.000 105.100 0.200 105.300 ;
    END
  END RW0_rdata[55]
  PIN RW0_rdata[54]
    DIRECTION OUTPUT ;
    USE SIGNAL ;
    PORT
      LAYER met4 ;
        RECT 0.000 105.500 0.200 105.700 ;
    END
  END RW0_rdata[54]
  PIN RW0_rdata[53]
    DIRECTION OUTPUT ;
    USE SIGNAL ;
    PORT
      LAYER met4 ;
        RECT 0.000 105.900 0.200 106.100 ;
    END
  END RW0_rdata[53]
  PIN RW0_rdata[52]
    DIRECTION OUTPUT ;
    USE SIGNAL ;
    PORT
      LAYER met4 ;
        RECT 0.000 106.300 0.200 106.500 ;
    END
  END RW0_rdata[52]
  PIN RW0_rdata[51]
    DIRECTION OUTPUT ;
    USE SIGNAL ;
    PORT
      LAYER met4 ;
        RECT 0.000 106.700 0.200 106.900 ;
    END
  END RW0_rdata[51]
  PIN RW0_rdata[50]
    DIRECTION OUTPUT ;
    USE SIGNAL ;
    PORT
      LAYER met4 ;
        RECT 0.000 107.100 0.200 107.300 ;
    END
  END RW0_rdata[50]
  PIN RW0_rdata[49]
    DIRECTION OUTPUT ;
    USE SIGNAL ;
    PORT
      LAYER met4 ;
        RECT 0.000 107.500 0.200 107.700 ;
    END
  END RW0_rdata[49]
  PIN RW0_rdata[48]
    DIRECTION OUTPUT ;
    USE SIGNAL ;
    PORT
      LAYER met4 ;
        RECT 0.000 107.900 0.200 108.100 ;
    END
  END RW0_rdata[48]
  PIN RW0_rdata[47]
    DIRECTION OUTPUT ;
    USE SIGNAL ;
    PORT
      LAYER met4 ;
        RECT 0.000 108.300 0.200 108.500 ;
    END
  END RW0_rdata[47]
  PIN RW0_rdata[46]
    DIRECTION OUTPUT ;
    USE SIGNAL ;
    PORT
      LAYER met4 ;
        RECT 0.000 108.700 0.200 108.900 ;
    END
  END RW0_rdata[46]
  PIN RW0_rdata[45]
    DIRECTION OUTPUT ;
    USE SIGNAL ;
    PORT
      LAYER met4 ;
        RECT 0.000 109.100 0.200 109.300 ;
    END
  END RW0_rdata[45]
  PIN RW0_rdata[44]
    DIRECTION OUTPUT ;
    USE SIGNAL ;
    PORT
      LAYER met4 ;
        RECT 0.000 109.500 0.200 109.700 ;
    END
  END RW0_rdata[44]
  PIN RW0_rdata[43]
    DIRECTION OUTPUT ;
    USE SIGNAL ;
    PORT
      LAYER met4 ;
        RECT 0.000 109.900 0.200 110.100 ;
    END
  END RW0_rdata[43]
  PIN RW0_rdata[42]
    DIRECTION OUTPUT ;
    USE SIGNAL ;
    PORT
      LAYER met4 ;
        RECT 0.000 110.300 0.200 110.500 ;
    END
  END RW0_rdata[42]
  PIN RW0_rdata[41]
    DIRECTION OUTPUT ;
    USE SIGNAL ;
    PORT
      LAYER met4 ;
        RECT 0.000 110.700 0.200 110.900 ;
    END
  END RW0_rdata[41]
  PIN RW0_rdata[40]
    DIRECTION OUTPUT ;
    USE SIGNAL ;
    PORT
      LAYER met4 ;
        RECT 0.000 111.100 0.200 111.300 ;
    END
  END RW0_rdata[40]
  PIN RW0_rdata[39]
    DIRECTION OUTPUT ;
    USE SIGNAL ;
    PORT
      LAYER met4 ;
        RECT 0.000 111.500 0.200 111.700 ;
    END
  END RW0_rdata[39]
  PIN RW0_rdata[38]
    DIRECTION OUTPUT ;
    USE SIGNAL ;
    PORT
      LAYER met4 ;
        RECT 0.000 111.900 0.200 112.100 ;
    END
  END RW0_rdata[38]
  PIN RW0_rdata[37]
    DIRECTION OUTPUT ;
    USE SIGNAL ;
    PORT
      LAYER met4 ;
        RECT 0.000 112.300 0.200 112.500 ;
    END
  END RW0_rdata[37]
  PIN RW0_rdata[36]
    DIRECTION OUTPUT ;
    USE SIGNAL ;
    PORT
      LAYER met4 ;
        RECT 0.000 112.700 0.200 112.900 ;
    END
  END RW0_rdata[36]
  PIN RW0_rdata[35]
    DIRECTION OUTPUT ;
    USE SIGNAL ;
    PORT
      LAYER met4 ;
        RECT 0.000 113.100 0.200 113.300 ;
    END
  END RW0_rdata[35]
  PIN RW0_rdata[34]
    DIRECTION OUTPUT ;
    USE SIGNAL ;
    PORT
      LAYER met4 ;
        RECT 0.000 113.500 0.200 113.700 ;
    END
  END RW0_rdata[34]
  PIN RW0_rdata[33]
    DIRECTION OUTPUT ;
    USE SIGNAL ;
    PORT
      LAYER met4 ;
        RECT 0.000 113.900 0.200 114.100 ;
    END
  END RW0_rdata[33]
  PIN RW0_rdata[32]
    DIRECTION OUTPUT ;
    USE SIGNAL ;
    PORT
      LAYER met4 ;
        RECT 0.000 114.300 0.200 114.500 ;
    END
  END RW0_rdata[32]
  PIN RW0_rdata[31]
    DIRECTION OUTPUT ;
    USE SIGNAL ;
    PORT
      LAYER met4 ;
        RECT 0.000 114.700 0.200 114.900 ;
    END
  END RW0_rdata[31]
  PIN RW0_rdata[30]
    DIRECTION OUTPUT ;
    USE SIGNAL ;
    PORT
      LAYER met4 ;
        RECT 0.000 115.100 0.200 115.300 ;
    END
  END RW0_rdata[30]
  PIN RW0_rdata[29]
    DIRECTION OUTPUT ;
    USE SIGNAL ;
    PORT
      LAYER met4 ;
        RECT 0.000 115.500 0.200 115.700 ;
    END
  END RW0_rdata[29]
  PIN RW0_rdata[28]
    DIRECTION OUTPUT ;
    USE SIGNAL ;
    PORT
      LAYER met4 ;
        RECT 0.000 115.900 0.200 116.100 ;
    END
  END RW0_rdata[28]
  PIN RW0_rdata[27]
    DIRECTION OUTPUT ;
    USE SIGNAL ;
    PORT
      LAYER met4 ;
        RECT 0.000 116.300 0.200 116.500 ;
    END
  END RW0_rdata[27]
  PIN RW0_rdata[26]
    DIRECTION OUTPUT ;
    USE SIGNAL ;
    PORT
      LAYER met4 ;
        RECT 0.000 116.700 0.200 116.900 ;
    END
  END RW0_rdata[26]
  PIN RW0_rdata[25]
    DIRECTION OUTPUT ;
    USE SIGNAL ;
    PORT
      LAYER met4 ;
        RECT 0.000 117.100 0.200 117.300 ;
    END
  END RW0_rdata[25]
  PIN RW0_rdata[24]
    DIRECTION OUTPUT ;
    USE SIGNAL ;
    PORT
      LAYER met4 ;
        RECT 0.000 117.500 0.200 117.700 ;
    END
  END RW0_rdata[24]
  PIN RW0_rdata[23]
    DIRECTION OUTPUT ;
    USE SIGNAL ;
    PORT
      LAYER met4 ;
        RECT 0.000 117.900 0.200 118.100 ;
    END
  END RW0_rdata[23]
  PIN RW0_rdata[22]
    DIRECTION OUTPUT ;
    USE SIGNAL ;
    PORT
      LAYER met4 ;
        RECT 0.000 118.300 0.200 118.500 ;
    END
  END RW0_rdata[22]
  PIN RW0_rdata[21]
    DIRECTION OUTPUT ;
    USE SIGNAL ;
    PORT
      LAYER met4 ;
        RECT 0.000 118.700 0.200 118.900 ;
    END
  END RW0_rdata[21]
  PIN RW0_rdata[20]
    DIRECTION OUTPUT ;
    USE SIGNAL ;
    PORT
      LAYER met4 ;
        RECT 0.000 119.100 0.200 119.300 ;
    END
  END RW0_rdata[20]
  PIN RW0_rdata[19]
    DIRECTION OUTPUT ;
    USE SIGNAL ;
    PORT
      LAYER met4 ;
        RECT 0.000 119.500 0.200 119.700 ;
    END
  END RW0_rdata[19]
  PIN RW0_rdata[18]
    DIRECTION OUTPUT ;
    USE SIGNAL ;
    PORT
      LAYER met4 ;
        RECT 0.000 119.900 0.200 120.100 ;
    END
  END RW0_rdata[18]
  PIN RW0_rdata[17]
    DIRECTION OUTPUT ;
    USE SIGNAL ;
    PORT
      LAYER met4 ;
        RECT 0.000 120.300 0.200 120.500 ;
    END
  END RW0_rdata[17]
  PIN RW0_rdata[16]
    DIRECTION OUTPUT ;
    USE SIGNAL ;
    PORT
      LAYER met4 ;
        RECT 0.000 120.700 0.200 120.900 ;
    END
  END RW0_rdata[16]
  PIN RW0_rdata[15]
    DIRECTION OUTPUT ;
    USE SIGNAL ;
    PORT
      LAYER met4 ;
        RECT 0.000 121.100 0.200 121.300 ;
    END
  END RW0_rdata[15]
  PIN RW0_rdata[14]
    DIRECTION OUTPUT ;
    USE SIGNAL ;
    PORT
      LAYER met4 ;
        RECT 0.000 121.500 0.200 121.700 ;
    END
  END RW0_rdata[14]
  PIN RW0_rdata[13]
    DIRECTION OUTPUT ;
    USE SIGNAL ;
    PORT
      LAYER met4 ;
        RECT 0.000 121.900 0.200 122.100 ;
    END
  END RW0_rdata[13]
  PIN RW0_rdata[12]
    DIRECTION OUTPUT ;
    USE SIGNAL ;
    PORT
      LAYER met4 ;
        RECT 0.000 122.300 0.200 122.500 ;
    END
  END RW0_rdata[12]
  PIN RW0_rdata[11]
    DIRECTION OUTPUT ;
    USE SIGNAL ;
    PORT
      LAYER met4 ;
        RECT 0.000 122.700 0.200 122.900 ;
    END
  END RW0_rdata[11]
  PIN RW0_rdata[10]
    DIRECTION OUTPUT ;
    USE SIGNAL ;
    PORT
      LAYER met4 ;
        RECT 0.000 123.100 0.200 123.300 ;
    END
  END RW0_rdata[10]
  PIN RW0_rdata[9]
    DIRECTION OUTPUT ;
    USE SIGNAL ;
    PORT
      LAYER met4 ;
        RECT 0.000 123.500 0.200 123.700 ;
    END
  END RW0_rdata[9]
  PIN RW0_rdata[8]
    DIRECTION OUTPUT ;
    USE SIGNAL ;
    PORT
      LAYER met4 ;
        RECT 0.000 123.900 0.200 124.100 ;
    END
  END RW0_rdata[8]
  PIN RW0_rdata[7]
    DIRECTION OUTPUT ;
    USE SIGNAL ;
    PORT
      LAYER met4 ;
        RECT 0.000 124.300 0.200 124.500 ;
    END
  END RW0_rdata[7]
  PIN RW0_rdata[6]
    DIRECTION OUTPUT ;
    USE SIGNAL ;
    PORT
      LAYER met4 ;
        RECT 0.000 124.700 0.200 124.900 ;
    END
  END RW0_rdata[6]
  PIN RW0_rdata[5]
    DIRECTION OUTPUT ;
    USE SIGNAL ;
    PORT
      LAYER met4 ;
        RECT 0.000 125.100 0.200 125.300 ;
    END
  END RW0_rdata[5]
  PIN RW0_rdata[4]
    DIRECTION OUTPUT ;
    USE SIGNAL ;
    PORT
      LAYER met4 ;
        RECT 0.000 125.500 0.200 125.700 ;
    END
  END RW0_rdata[4]
  PIN RW0_rdata[3]
    DIRECTION OUTPUT ;
    USE SIGNAL ;
    PORT
      LAYER met4 ;
        RECT 0.000 125.900 0.200 126.100 ;
    END
  END RW0_rdata[3]
  PIN RW0_rdata[2]
    DIRECTION OUTPUT ;
    USE SIGNAL ;
    PORT
      LAYER met4 ;
        RECT 0.000 126.300 0.200 126.500 ;
    END
  END RW0_rdata[2]
  PIN RW0_rdata[1]
    DIRECTION OUTPUT ;
    USE SIGNAL ;
    PORT
      LAYER met4 ;
        RECT 0.000 126.700 0.200 126.900 ;
    END
  END RW0_rdata[1]
  PIN RW0_rdata[0]
    DIRECTION OUTPUT ;
    USE SIGNAL ;
    PORT
      LAYER met4 ;
        RECT 0.000 127.100 0.200 127.300 ;
    END
  END RW0_rdata[0]
  PIN RW0_wmask[7]
    DIRECTION INPUT ;
    USE SIGNAL ;
    PORT
      LAYER met4 ;
        RECT 0.000 127.500 0.200 127.700 ;
    END
  END RW0_wmask[7]
  PIN RW0_wmask[6]
    DIRECTION INPUT ;
    USE SIGNAL ;
    PORT
      LAYER met4 ;
        RECT 0.000 127.900 0.200 128.100 ;
    END
  END RW0_wmask[6]
  PIN RW0_wmask[5]
    DIRECTION INPUT ;
    USE SIGNAL ;
    PORT
      LAYER met4 ;
        RECT 0.000 128.300 0.200 128.500 ;
    END
  END RW0_wmask[5]
  PIN RW0_wmask[4]
    DIRECTION INPUT ;
    USE SIGNAL ;
    PORT
      LAYER met4 ;
        RECT 0.000 128.700 0.200 128.900 ;
    END
  END RW0_wmask[4]
  PIN RW0_wmask[3]
    DIRECTION INPUT ;
    USE SIGNAL ;
    PORT
      LAYER met4 ;
        RECT 0.000 129.100 0.200 129.300 ;
    END
  END RW0_wmask[3]
  PIN RW0_wmask[2]
    DIRECTION INPUT ;
    USE SIGNAL ;
    PORT
      LAYER met4 ;
        RECT 0.000 129.500 0.200 129.700 ;
    END
  END RW0_wmask[2]
  PIN RW0_wmask[1]
    DIRECTION INPUT ;
    USE SIGNAL ;
    PORT
      LAYER met4 ;
        RECT 0.000 129.900 0.200 130.100 ;
    END
  END RW0_wmask[1]
  PIN RW0_wmask[0]
    DIRECTION INPUT ;
    USE SIGNAL ;
    PORT
      LAYER met4 ;
        RECT 0.000 130.300 0.200 130.500 ;
    END
  END RW0_wmask[0]
  OBS
    LAYER met1 ;
      RECT 0.000 0.000 177.615 1516.040 ;
    LAYER met2 ;
      RECT 0.000 0.000 177.615 1516.040 ;
    LAYER met3 ;
      RECT 0.000 0.000 177.615 1516.040 ;
  END
END cacti_cc_dir_ext

END LIBRARY
